# Hand-written LEF in the style of NanGate45 + fakeram45
VERSION 5.8 ;
BUSBITCHARS "[]" ;
DIVIDERCHAR "/" ;

UNITS
  DATABASE MICRONS 2000 ;
END UNITS

MANUFACTURINGGRID 0.005 ;

PROPERTYDEFINITIONS
  LAYER LEF58_TYPE STRING ;
END PROPERTYDEFINITIONS

LAYER metal1
  TYPE ROUTING ;
  DIRECTION HORIZONTAL ;
  PITCH 0.14 ;
  WIDTH 0.07 ;
  PROPERTY LEF58_TYPE "TYPE ROUTING ; # not a comment" ;
END metal1

LAYER via1
  TYPE CUT ;
END via1

VIA via1_4 DEFAULT
  LAYER metal1 ;
    RECT -0.035 -0.065 0.035 0.065 ;
END via1_4

SITE FreePDK45_38x28_10R_NP_162NW_34O
  SYMMETRY y ;
  CLASS core ;
  SIZE 0.19 BY 1.4 ;
END FreePDK45_38x28_10R_NP_162NW_34O

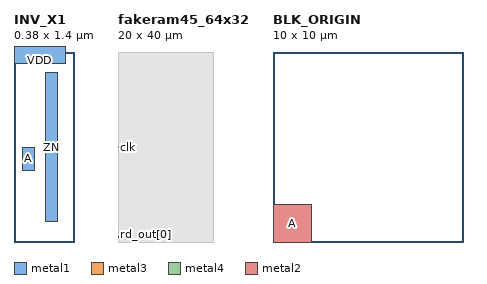
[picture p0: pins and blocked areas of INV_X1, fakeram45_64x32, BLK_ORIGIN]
MACRO INV_X1
  CLASS CORE ;
  ORIGIN 0 0 ;
  FOREIGN INV_X1 0 0 ;
  SIZE 0.38 BY 1.4 ;
  SYMMETRY X Y ;
  SITE FreePDK45_38x28_10R_NP_162NW_34O ;
  PIN A
    DIRECTION INPUT ;
    ANTENNAPARTIALMETALAREA 0.02 LAYER metal1 ;
    PORT
      LAYER metal1 ;
        POLYGON 0.06 0.525 0.15 0.525 0.15 0.7 0.06 0.7 ;
    END
  END A
  PIN ZN
    DIRECTION OUTPUT ;
    PORT
      LAYER metal1 ;
        RECT 0.23 0.15 0.32 1.25 ;
    END
  END ZN
  PIN VDD
    DIRECTION INOUT ;
    USE power ;
    SHAPE ABUTMENT ;
    PORT
      LAYER metal1 ;
        RECT 0 1.315 0.38 1.485 ;
    END
  END VDD
END INV_X1

MACRO fakeram45_64x32
  FOREIGN fakeram45_64x32 0 0 ;
  SYMMETRY X Y R90 ;
  SIZE 20.000 BY 40.000 ;
  CLASS BLOCK ;
  PIN clk
    DIRECTION INPUT ;
    USE SIGNAL ;
    SHAPE ABUTMENT ;
    PORT
      LAYER metal3 ;
      RECT 0.000 19.950 0.070 20.050 ;
    END
  END clk
  PIN rd_out[0]
    DIRECTION OUTPUT ;
    USE SIGNAL ;
    PORT
      LAYER metal3 ;
      RECT MASK 1 0.000 1.000 0.100 1.200 ;
      LAYER metal4 ;
      RECT 0.000 0.900 0.200 1.100 ;
    END
  END rd_out[0]
  OBS
    LAYER metal1 ;
    RECT 0 0 20.000 40.000 ;
    LAYER OVERLAP ;
    RECT 0 0 20.000 40.000 ;
  END
END fakeram45_64x32

MACRO BLK_ORIGIN
  CLASS BLOCK ;
  ORIGIN 1 2 ;
  SIZE 10 BY 10 ;
  PIN A
    DIRECTION INPUT ;
    PORT
      LAYER metal2 ;
      RECT -1 -2 1 0 ;
    END
  END A
END BLK_ORIGIN

END LIBRARY
